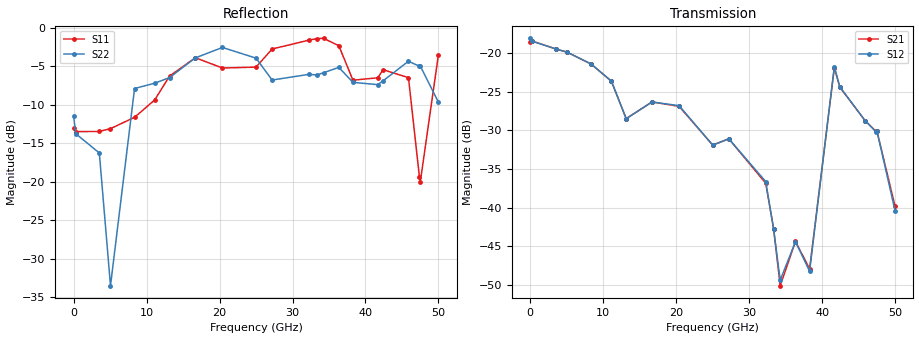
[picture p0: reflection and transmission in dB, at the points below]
!Keysight Technologies,N5245B,MY58422270,A.16.20.02
!Date: Thursday, March 05, 2026 01:20:43
!Correction: S11(C  2-Port  )
!S21(C  2-Port  )
!S12(C  2-Port  )
!S22(C  2-Port  )
!S2P File: Measurements: S11, S21, S12, S22:
# Hz S  dB  R 50
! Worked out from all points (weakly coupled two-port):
!   3201 points, 10 MHz to 50 GHz, reference 50 ohm
!   highest |S21| = -18.47 dB at 275.6 MHz (marker M1); lowest = -50.1 dB at 34.25 GHz (marker M2)
!   lowest |S11| = -20.0 dB at 47.52 GHz (marker M3), VSWR 1.22, Z = 45.7 + j8.56 ohm
!   |S11| at or under -10 dB: start of sweep to 10.16 GHz; 11.35 GHz to 11.92 GHz (573 MHz wide, 4.92 % of centre); 46.66 GHz to 48.29 GHz (1.628 GHz wide, 3.43 % of centre)
!   |S22| runs from -33.5 to -2.5 dB; largest |S21 - S12| = 0.0074
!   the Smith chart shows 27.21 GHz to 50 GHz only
!   S11 on the Smith chart (normalised r, x): 27.21 GHz: 0.18, +0.36; 32.27 GHz: 0.42, +1.83; 36.35 GHz: 2.45, -3.41; 42.42 GHz: 1.01, -1.27; 47.39 GHz: 0.84, +0.12; 50 GHz: 0.62, -1.35
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1e7  -12.99 -3.6  -18.56 4.6  -18.13 3.9  -11.47 27.1
2.755719e8  -13.49 -11.9  -18.47 -10.9  -18.51 -11.1  -13.75 -14.7
3.524922e9  -13.48 -93.0  -19.51 -136.2  -19.50 -136.2  -16.27 -165.9
5.055866e9  -13.11 -125.3  -19.92 162.7  -19.91 162.5  -33.50 50.1
8.352081e9  -11.64 174.6  -21.45 24.9  -21.45 24.9  -7.90 -148.7
1.111715e10  -9.38 108.3  -23.67 -81.2  -23.65 -81.2  -7.21 95.4
1.3148e10  -6.29 64.9  -28.49 -141.1  -28.51 -141.0  -6.48 -16.2
1.667854e10  -3.90 -43.8  -26.34 155.8  -26.35 155.9  -3.93 -139.4
2.039655e10  -5.24 -121.2  -26.91 40.1  -26.82 40.0  -2.57 155.7
2.5005e10  -5.12 179.6  -31.91 -64.9  -31.92 -64.5  -3.96 71.4
2.720768e10  -2.77 139.2  -31.10 -114.3  -31.10 -113.9  -6.80 31.9
3.226917e10  -1.62 55.3  -36.84 50.3  -36.62 50.7  -6.06 -102.2
3.334708e10  -1.42 36.1  -42.69 6.5  -42.75 6.2  -6.14 -125.8
3.425315e10  -1.39 20.0  -50.07 -69.7  -49.35 -65.9  -5.85 -144.7
3.634648e10  -2.34 -22.3  -44.35 114.7  -44.39 112.0  -5.16 175.4
3.828359e10  -6.82 -22.3  -47.89 92.8  -48.20 42.4  -7.10 139.4
4.167354e10  -6.51 -52.7  -21.91 -59.6  -21.78 -59.1  -7.40 118.1
4.242339e10  -5.46 -57.3  -24.44 -119.9  -24.39 -119.9  -6.90 113.8
4.589145e10  -6.49 -117.2  -28.76 55.0  -28.76 54.8  -4.36 62.8
4.739115e10  -19.34 140.1  -30.15 4.8  -30.20 4.7  -5.00 42.4
4.751612e10  -20.02 111.5  -30.11 3.0  -30.11 2.3  -4.99 40.9
5e10  -3.52 -65.9  -39.84 -135.3  -40.41 -141.4  -9.68 3.1
